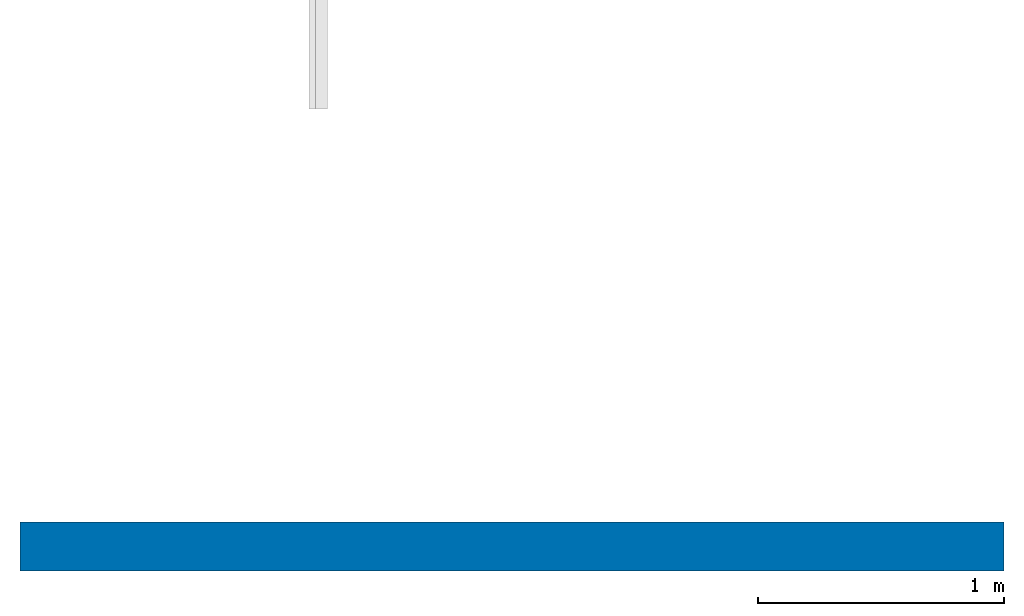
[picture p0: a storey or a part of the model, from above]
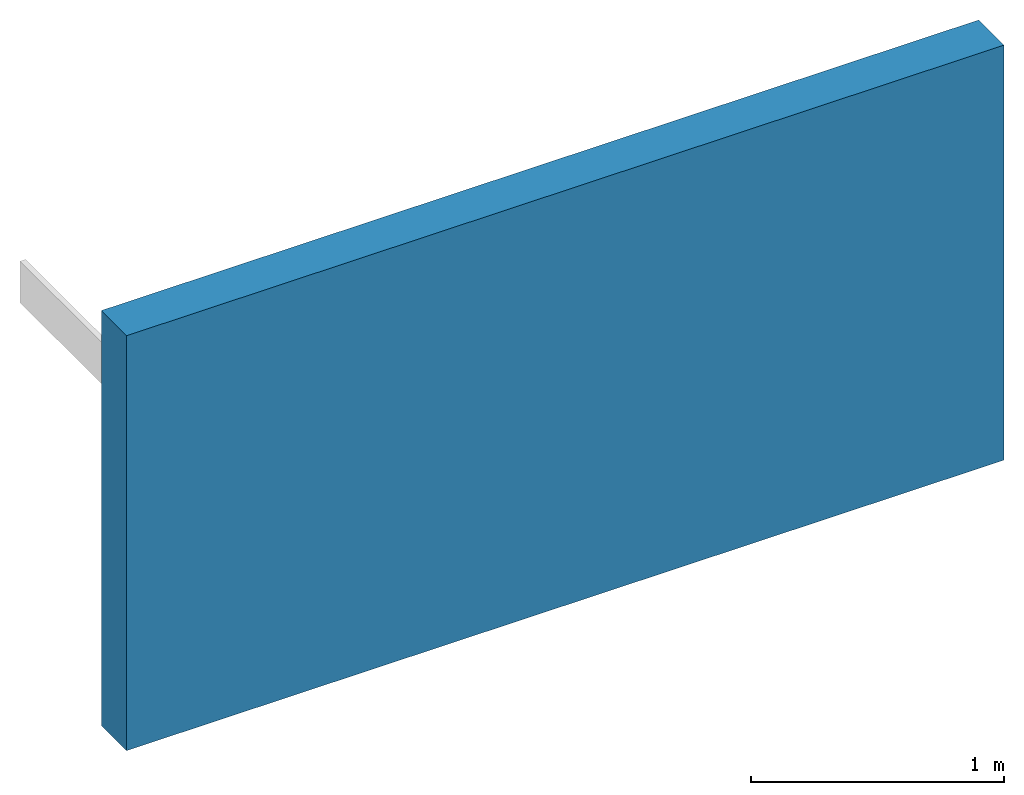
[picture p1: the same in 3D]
Properties of the parts of a building model (IFC2X3)

# File
Description: ViewDefinition [CoordinationView_V2.0]
File name: Project Number
Time: 2019-04-24T12:17:36
Written by: The EXPRESS Data Manager Version 5.02.0100.07 : 28 Aug 2013
Made in: 20181011_1500(x64) - Exporter 18.3.2.7 - Alternate UI 18.3.2.7
Comment: STEP Physical File produced by: The EXPRESS Data Manager Version 5.02.0100.07 : 28 Aug 2013 * Module: EDMstepFileFactory/EDMstandAlone * Creation date: Wed Apr 24 12:17:36 2019 * Host: Fanie * Database: C:\Users\Fanie\AppData\Local\Temp\{F87BCB44-B2D5-4EA4-8CA4-EC76E6CE70C8}\ifc * Database version: 5507 * Database creation date: Wed Apr 24 12:17:35 2019 * Schema: IFC2X3 * Model: DataRepository.ifc * Model creation date: Wed Apr 24 12:17:35 2019 * Header model: DataRepository.ifc_HeaderModel * Header model creation date: Wed Apr 24 12:17:35 2019 * EDMuser: sdai-user * EDMgroup: sdai-group * License ID and type: 5605 : Permanent license. Expiry date: * EDMstepFileFactory options: 020000

# IfcProject, Project Number
LongName: Project Name; Phase: Project Status

# IfcSite, Default
RefLatitude: 42, 21, 31, 181945; RefLongitude: -71, -3, -24, -263305; RefElevation: 0 mm

# IfcBuilding
Pset_BuildingCommon - NumberOfStoreys: 1

# IfcBuildingStorey, Level 1
LongName: Level 1; Elevation: 0 mm

# IfcBuildingElementProxy: Bond-Lok FD1-Kerb Flashing, Bond-lok Kerb Flashing Family:Bond-Lok FD1-Kerb Flashing:203684
In: Level 1
Type - Material: ISQ 300, Galvanized Z275
Pset_BuildingElementProxyCommon - Reference: Bond-Lok FD1-Kerb Flashing
Pset_ManufacturerTypeInformation - Manufacturer: Global Roofing Solutions

# IfcWallStandardCase: Basic Wall:Generic - 200mm, Basic Wall:Generic - 200mm:201838
In: Level 1
Type - PredefinedType: STANDARD; Material: Default Wall 200 mm
Pset_WallCommon - Reference: Generic - 200mm; LoadBearing: no; ExtendToStructure: no; IsExternal: yes
